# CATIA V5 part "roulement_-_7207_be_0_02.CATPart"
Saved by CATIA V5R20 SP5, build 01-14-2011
Part number: roulement_-_7207_be_0_02
Bounding box of the stored display mesh (mm): x 0 to 17, y -24.353 to 24.353, z -24.353 to 24.353
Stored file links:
  C:\DOCUME~1\hermantg\LOCALS~1\Temp\Trace Parts\roulement_-_7207_be_0_02.CATPart

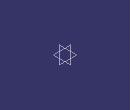
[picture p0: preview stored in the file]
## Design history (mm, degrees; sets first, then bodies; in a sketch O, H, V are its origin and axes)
AxisSystem1: origin (0, 0, 0), X (1, 0, 0), Y (0, 1, 0), Z (0, 0, 1)
Body1 "roulement_-_7207_be_0_02" (main body)
  Solid1: solid without history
